VERSION 5.7 ;
BUSBITCHARS "[]" ;
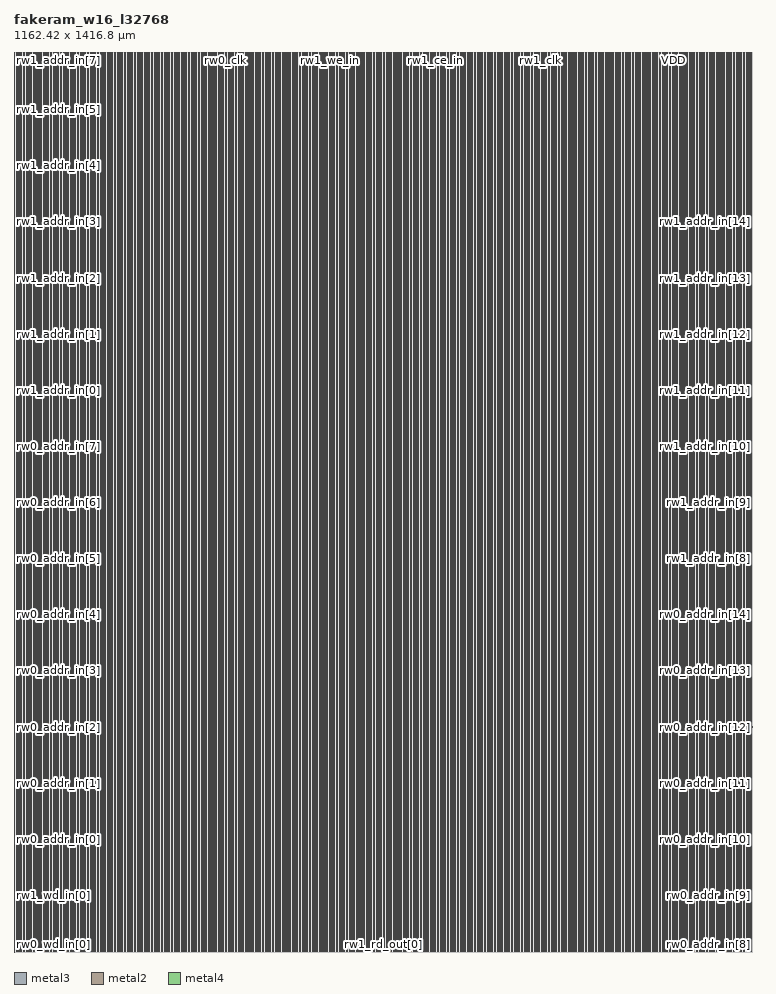
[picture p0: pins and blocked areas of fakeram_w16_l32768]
MACRO fakeram_w16_l32768
  FOREIGN fakeram_w16_l32768 0 0 ;
  SYMMETRY X Y R90 ;
  SIZE 1162.420 BY 1416.800 ;
  CLASS BLOCK ;
  PIN rw0_wd_in[0]
    DIRECTION INPUT ;
    USE SIGNAL ;
    SHAPE ABUTMENT ;
    PORT
      LAYER metal3 ;
      RECT 0.000 0.805 0.210 0.875 ;
    END
  END rw0_wd_in[0]
  PIN rw1_wd_in[0]
    DIRECTION INPUT ;
    USE SIGNAL ;
    SHAPE ABUTMENT ;
    PORT
      LAYER metal3 ;
      RECT 0.000 89.145 0.210 89.215 ;
    END
  END rw1_wd_in[0]
  PIN rw0_rd_out[0]
    DIRECTION OUTPUT ;
    USE SIGNAL ;
    SHAPE ABUTMENT ;
    PORT
      LAYER metal2 ;
      RECT 1.105 0.000 1.175 0.210 ;
    END
  END rw0_rd_out[0]
  PIN rw1_rd_out[0]
    DIRECTION OUTPUT ;
    USE SIGNAL ;
    SHAPE ABUTMENT ;
    PORT
      LAYER metal2 ;
      RECT 580.985 0.000 581.055 0.210 ;
    END
  END rw1_rd_out[0]
  PIN rw0_addr_in[0]
    DIRECTION INPUT ;
    USE SIGNAL ;
    SHAPE ABUTMENT ;
    PORT
      LAYER metal3 ;
      RECT 0.000 177.485 0.210 177.555 ;
    END
  END rw0_addr_in[0]
  PIN rw0_addr_in[1]
    DIRECTION INPUT ;
    USE SIGNAL ;
    SHAPE ABUTMENT ;
    PORT
      LAYER metal3 ;
      RECT 0.000 265.825 0.210 265.895 ;
    END
  END rw0_addr_in[1]
  PIN rw0_addr_in[2]
    DIRECTION INPUT ;
    USE SIGNAL ;
    SHAPE ABUTMENT ;
    PORT
      LAYER metal3 ;
      RECT 0.000 354.165 0.210 354.235 ;
    END
  END rw0_addr_in[2]
  PIN rw0_addr_in[3]
    DIRECTION INPUT ;
    USE SIGNAL ;
    SHAPE ABUTMENT ;
    PORT
      LAYER metal3 ;
      RECT 0.000 442.505 0.210 442.575 ;
    END
  END rw0_addr_in[3]
  PIN rw0_addr_in[4]
    DIRECTION INPUT ;
    USE SIGNAL ;
    SHAPE ABUTMENT ;
    PORT
      LAYER metal3 ;
      RECT 0.000 530.845 0.210 530.915 ;
    END
  END rw0_addr_in[4]
  PIN rw0_addr_in[5]
    DIRECTION INPUT ;
    USE SIGNAL ;
    SHAPE ABUTMENT ;
    PORT
      LAYER metal3 ;
      RECT 0.000 619.185 0.210 619.255 ;
    END
  END rw0_addr_in[5]
  PIN rw0_addr_in[6]
    DIRECTION INPUT ;
    USE SIGNAL ;
    SHAPE ABUTMENT ;
    PORT
      LAYER metal3 ;
      RECT 0.000 707.525 0.210 707.595 ;
    END
  END rw0_addr_in[6]
  PIN rw0_addr_in[7]
    DIRECTION INPUT ;
    USE SIGNAL ;
    SHAPE ABUTMENT ;
    PORT
      LAYER metal3 ;
      RECT 0.000 795.865 0.210 795.935 ;
    END
  END rw0_addr_in[7]
  PIN rw0_addr_in[8]
    DIRECTION INPUT ;
    USE SIGNAL ;
    SHAPE ABUTMENT ;
    PORT
      LAYER metal3 ;
      RECT 1162.210 0.805 1162.420 0.875 ;
    END
  END rw0_addr_in[8]
  PIN rw0_addr_in[9]
    DIRECTION INPUT ;
    USE SIGNAL ;
    SHAPE ABUTMENT ;
    PORT
      LAYER metal3 ;
      RECT 1162.210 89.145 1162.420 89.215 ;
    END
  END rw0_addr_in[9]
  PIN rw0_addr_in[10]
    DIRECTION INPUT ;
    USE SIGNAL ;
    SHAPE ABUTMENT ;
    PORT
      LAYER metal3 ;
      RECT 1162.210 177.485 1162.420 177.555 ;
    END
  END rw0_addr_in[10]
  PIN rw0_addr_in[11]
    DIRECTION INPUT ;
    USE SIGNAL ;
    SHAPE ABUTMENT ;
    PORT
      LAYER metal3 ;
      RECT 1162.210 265.825 1162.420 265.895 ;
    END
  END rw0_addr_in[11]
  PIN rw0_addr_in[12]
    DIRECTION INPUT ;
    USE SIGNAL ;
    SHAPE ABUTMENT ;
    PORT
      LAYER metal3 ;
      RECT 1162.210 354.165 1162.420 354.235 ;
    END
  END rw0_addr_in[12]
  PIN rw0_addr_in[13]
    DIRECTION INPUT ;
    USE SIGNAL ;
    SHAPE ABUTMENT ;
    PORT
      LAYER metal3 ;
      RECT 1162.210 442.505 1162.420 442.575 ;
    END
  END rw0_addr_in[13]
  PIN rw0_addr_in[14]
    DIRECTION INPUT ;
    USE SIGNAL ;
    SHAPE ABUTMENT ;
    PORT
      LAYER metal3 ;
      RECT 1162.210 530.845 1162.420 530.915 ;
    END
  END rw0_addr_in[14]
  PIN rw1_addr_in[0]
    DIRECTION INPUT ;
    USE SIGNAL ;
    SHAPE ABUTMENT ;
    PORT
      LAYER metal3 ;
      RECT 0.000 884.205 0.210 884.275 ;
    END
  END rw1_addr_in[0]
  PIN rw1_addr_in[1]
    DIRECTION INPUT ;
    USE SIGNAL ;
    SHAPE ABUTMENT ;
    PORT
      LAYER metal3 ;
      RECT 0.000 972.545 0.210 972.615 ;
    END
  END rw1_addr_in[1]
  PIN rw1_addr_in[2]
    DIRECTION INPUT ;
    USE SIGNAL ;
    SHAPE ABUTMENT ;
    PORT
      LAYER metal3 ;
      RECT 0.000 1060.885 0.210 1060.955 ;
    END
  END rw1_addr_in[2]
  PIN rw1_addr_in[3]
    DIRECTION INPUT ;
    USE SIGNAL ;
    SHAPE ABUTMENT ;
    PORT
      LAYER metal3 ;
      RECT 0.000 1149.225 0.210 1149.295 ;
    END
  END rw1_addr_in[3]
  PIN rw1_addr_in[4]
    DIRECTION INPUT ;
    USE SIGNAL ;
    SHAPE ABUTMENT ;
    PORT
      LAYER metal3 ;
      RECT 0.000 1237.565 0.210 1237.635 ;
    END
  END rw1_addr_in[4]
  PIN rw1_addr_in[5]
    DIRECTION INPUT ;
    USE SIGNAL ;
    SHAPE ABUTMENT ;
    PORT
      LAYER metal3 ;
      RECT 0.000 1325.905 0.210 1325.975 ;
    END
  END rw1_addr_in[5]
  PIN rw1_addr_in[6]
    DIRECTION INPUT ;
    USE SIGNAL ;
    SHAPE ABUTMENT ;
    PORT
      LAYER metal3 ;
      RECT 0.000 1414.245 0.210 1414.315 ;
    END
  END rw1_addr_in[6]
  PIN rw1_addr_in[7]
    DIRECTION INPUT ;
    USE SIGNAL ;
    SHAPE ABUTMENT ;
    PORT
      LAYER metal3 ;
      RECT 0.000 1502.585 0.210 1502.655 ;
    END
  END rw1_addr_in[7]
  PIN rw1_addr_in[8]
    DIRECTION INPUT ;
    USE SIGNAL ;
    SHAPE ABUTMENT ;
    PORT
      LAYER metal3 ;
      RECT 1162.210 619.185 1162.420 619.255 ;
    END
  END rw1_addr_in[8]
  PIN rw1_addr_in[9]
    DIRECTION INPUT ;
    USE SIGNAL ;
    SHAPE ABUTMENT ;
    PORT
      LAYER metal3 ;
      RECT 1162.210 707.525 1162.420 707.595 ;
    END
  END rw1_addr_in[9]
  PIN rw1_addr_in[10]
    DIRECTION INPUT ;
    USE SIGNAL ;
    SHAPE ABUTMENT ;
    PORT
      LAYER metal3 ;
      RECT 1162.210 795.865 1162.420 795.935 ;
    END
  END rw1_addr_in[10]
  PIN rw1_addr_in[11]
    DIRECTION INPUT ;
    USE SIGNAL ;
    SHAPE ABUTMENT ;
    PORT
      LAYER metal3 ;
      RECT 1162.210 884.205 1162.420 884.275 ;
    END
  END rw1_addr_in[11]
  PIN rw1_addr_in[12]
    DIRECTION INPUT ;
    USE SIGNAL ;
    SHAPE ABUTMENT ;
    PORT
      LAYER metal3 ;
      RECT 1162.210 972.545 1162.420 972.615 ;
    END
  END rw1_addr_in[12]
  PIN rw1_addr_in[13]
    DIRECTION INPUT ;
    USE SIGNAL ;
    SHAPE ABUTMENT ;
    PORT
      LAYER metal3 ;
      RECT 1162.210 1060.885 1162.420 1060.955 ;
    END
  END rw1_addr_in[13]
  PIN rw1_addr_in[14]
    DIRECTION INPUT ;
    USE SIGNAL ;
    SHAPE ABUTMENT ;
    PORT
      LAYER metal3 ;
      RECT 1162.210 1149.225 1162.420 1149.295 ;
    END
  END rw1_addr_in[14]
  PIN rw0_we_in
    DIRECTION INPUT ;
    USE SIGNAL ;
    SHAPE ABUTMENT ;
    PORT
      LAYER metal2 ;
      RECT 1.105 1416.590 1.175 1416.800 ;
    END
  END rw0_we_in
  PIN rw0_ce_in
    DIRECTION INPUT ;
    USE SIGNAL ;
    SHAPE ABUTMENT ;
    PORT
      LAYER metal2 ;
      RECT 166.785 1416.590 166.855 1416.800 ;
    END
  END rw0_ce_in
  PIN rw0_clk
    DIRECTION INPUT ;
    USE SIGNAL ;
    SHAPE ABUTMENT ;
    PORT
      LAYER metal2 ;
      RECT 332.465 1416.590 332.535 1416.800 ;
    END
  END rw0_clk
  PIN rw1_we_in
    DIRECTION INPUT ;
    USE SIGNAL ;
    SHAPE ABUTMENT ;
    PORT
      LAYER metal2 ;
      RECT 498.145 1416.590 498.215 1416.800 ;
    END
  END rw1_we_in
  PIN rw1_ce_in
    DIRECTION INPUT ;
    USE SIGNAL ;
    SHAPE ABUTMENT ;
    PORT
      LAYER metal2 ;
      RECT 663.825 1416.590 663.895 1416.800 ;
    END
  END rw1_ce_in
  PIN rw1_clk
    DIRECTION INPUT ;
    USE SIGNAL ;
    SHAPE ABUTMENT ;
    PORT
      LAYER metal2 ;
      RECT 829.505 1416.590 829.575 1416.800 ;
    END
  END rw1_clk
  PIN VSS
    DIRECTION INOUT ;
    USE GROUND ;
    PORT
      LAYER metal4 ;
      RECT 1.000 0.840 1.280 1415.960 ;
      RECT 3.240 0.840 3.520 1415.960 ;
      RECT 5.480 0.840 5.760 1415.960 ;
      RECT 7.720 0.840 8.000 1415.960 ;
      RECT 9.960 0.840 10.240 1415.960 ;
      RECT 12.200 0.840 12.480 1415.960 ;
      RECT 14.440 0.840 14.720 1415.960 ;
      RECT 16.680 0.840 16.960 1415.960 ;
      RECT 18.920 0.840 19.200 1415.960 ;
      RECT 21.160 0.840 21.440 1415.960 ;
      RECT 23.400 0.840 23.680 1415.960 ;
      RECT 25.640 0.840 25.920 1415.960 ;
      RECT 27.880 0.840 28.160 1415.960 ;
      RECT 30.120 0.840 30.400 1415.960 ;
      RECT 32.360 0.840 32.640 1415.960 ;
      RECT 34.600 0.840 34.880 1415.960 ;
      RECT 36.840 0.840 37.120 1415.960 ;
      RECT 39.080 0.840 39.360 1415.960 ;
      RECT 41.320 0.840 41.600 1415.960 ;
      RECT 43.560 0.840 43.840 1415.960 ;
      RECT 45.800 0.840 46.080 1415.960 ;
      RECT 48.040 0.840 48.320 1415.960 ;
      RECT 50.280 0.840 50.560 1415.960 ;
      RECT 52.520 0.840 52.800 1415.960 ;
      RECT 54.760 0.840 55.040 1415.960 ;
      RECT 57.000 0.840 57.280 1415.960 ;
      RECT 59.240 0.840 59.520 1415.960 ;
      RECT 61.480 0.840 61.760 1415.960 ;
      RECT 63.720 0.840 64.000 1415.960 ;
      RECT 65.960 0.840 66.240 1415.960 ;
      RECT 68.200 0.840 68.480 1415.960 ;
      RECT 70.440 0.840 70.720 1415.960 ;
      RECT 72.680 0.840 72.960 1415.960 ;
      RECT 74.920 0.840 75.200 1415.960 ;
      RECT 77.160 0.840 77.440 1415.960 ;
      RECT 79.400 0.840 79.680 1415.960 ;
      RECT 81.640 0.840 81.920 1415.960 ;
      RECT 83.880 0.840 84.160 1415.960 ;
      RECT 86.120 0.840 86.400 1415.960 ;
      RECT 88.360 0.840 88.640 1415.960 ;
      RECT 90.600 0.840 90.880 1415.960 ;
      RECT 92.840 0.840 93.120 1415.960 ;
      RECT 95.080 0.840 95.360 1415.960 ;
      RECT 97.320 0.840 97.600 1415.960 ;
      RECT 99.560 0.840 99.840 1415.960 ;
      RECT 101.800 0.840 102.080 1415.960 ;
      RECT 104.040 0.840 104.320 1415.960 ;
      RECT 106.280 0.840 106.560 1415.960 ;
      RECT 108.520 0.840 108.800 1415.960 ;
      RECT 110.760 0.840 111.040 1415.960 ;
      RECT 113.000 0.840 113.280 1415.960 ;
      RECT 115.240 0.840 115.520 1415.960 ;
      RECT 117.480 0.840 117.760 1415.960 ;
      RECT 119.720 0.840 120.000 1415.960 ;
      RECT 121.960 0.840 122.240 1415.960 ;
      RECT 124.200 0.840 124.480 1415.960 ;
      RECT 126.440 0.840 126.720 1415.960 ;
      RECT 128.680 0.840 128.960 1415.960 ;
      RECT 130.920 0.840 131.200 1415.960 ;
      RECT 133.160 0.840 133.440 1415.960 ;
      RECT 135.400 0.840 135.680 1415.960 ;
      RECT 137.640 0.840 137.920 1415.960 ;
      RECT 139.880 0.840 140.160 1415.960 ;
      RECT 142.120 0.840 142.400 1415.960 ;
      RECT 144.360 0.840 144.640 1415.960 ;
      RECT 146.600 0.840 146.880 1415.960 ;
      RECT 148.840 0.840 149.120 1415.960 ;
      RECT 151.080 0.840 151.360 1415.960 ;
      RECT 153.320 0.840 153.600 1415.960 ;
      RECT 155.560 0.840 155.840 1415.960 ;
      RECT 157.800 0.840 158.080 1415.960 ;
      RECT 160.040 0.840 160.320 1415.960 ;
      RECT 162.280 0.840 162.560 1415.960 ;
      RECT 164.520 0.840 164.800 1415.960 ;
      RECT 166.760 0.840 167.040 1415.960 ;
      RECT 169.000 0.840 169.280 1415.960 ;
      RECT 171.240 0.840 171.520 1415.960 ;
      RECT 173.480 0.840 173.760 1415.960 ;
      RECT 175.720 0.840 176.000 1415.960 ;
      RECT 177.960 0.840 178.240 1415.960 ;
      RECT 180.200 0.840 180.480 1415.960 ;
      RECT 182.440 0.840 182.720 1415.960 ;
      RECT 184.680 0.840 184.960 1415.960 ;
      RECT 186.920 0.840 187.200 1415.960 ;
      RECT 189.160 0.840 189.440 1415.960 ;
      RECT 191.400 0.840 191.680 1415.960 ;
      RECT 193.640 0.840 193.920 1415.960 ;
      RECT 195.880 0.840 196.160 1415.960 ;
      RECT 198.120 0.840 198.400 1415.960 ;
      RECT 200.360 0.840 200.640 1415.960 ;
      RECT 202.600 0.840 202.880 1415.960 ;
      RECT 204.840 0.840 205.120 1415.960 ;
      RECT 207.080 0.840 207.360 1415.960 ;
      RECT 209.320 0.840 209.600 1415.960 ;
      RECT 211.560 0.840 211.840 1415.960 ;
      RECT 213.800 0.840 214.080 1415.960 ;
      RECT 216.040 0.840 216.320 1415.960 ;
      RECT 218.280 0.840 218.560 1415.960 ;
      RECT 220.520 0.840 220.800 1415.960 ;
      RECT 222.760 0.840 223.040 1415.960 ;
      RECT 225.000 0.840 225.280 1415.960 ;
      RECT 227.240 0.840 227.520 1415.960 ;
      RECT 229.480 0.840 229.760 1415.960 ;
      RECT 231.720 0.840 232.000 1415.960 ;
      RECT 233.960 0.840 234.240 1415.960 ;
      RECT 236.200 0.840 236.480 1415.960 ;
      RECT 238.440 0.840 238.720 1415.960 ;
      RECT 240.680 0.840 240.960 1415.960 ;
      RECT 242.920 0.840 243.200 1415.960 ;
      RECT 245.160 0.840 245.440 1415.960 ;
      RECT 247.400 0.840 247.680 1415.960 ;
      RECT 249.640 0.840 249.920 1415.960 ;
      RECT 251.880 0.840 252.160 1415.960 ;
      RECT 254.120 0.840 254.400 1415.960 ;
      RECT 256.360 0.840 256.640 1415.960 ;
      RECT 258.600 0.840 258.880 1415.960 ;
      RECT 260.840 0.840 261.120 1415.960 ;
      RECT 263.080 0.840 263.360 1415.960 ;
      RECT 265.320 0.840 265.600 1415.960 ;
      RECT 267.560 0.840 267.840 1415.960 ;
      RECT 269.800 0.840 270.080 1415.960 ;
      RECT 272.040 0.840 272.320 1415.960 ;
      RECT 274.280 0.840 274.560 1415.960 ;
      RECT 276.520 0.840 276.800 1415.960 ;
      RECT 278.760 0.840 279.040 1415.960 ;
      RECT 281.000 0.840 281.280 1415.960 ;
      RECT 283.240 0.840 283.520 1415.960 ;
      RECT 285.480 0.840 285.760 1415.960 ;
      RECT 287.720 0.840 288.000 1415.960 ;
      RECT 289.960 0.840 290.240 1415.960 ;
      RECT 292.200 0.840 292.480 1415.960 ;
      RECT 294.440 0.840 294.720 1415.960 ;
      RECT 296.680 0.840 296.960 1415.960 ;
      RECT 298.920 0.840 299.200 1415.960 ;
      RECT 301.160 0.840 301.440 1415.960 ;
      RECT 303.400 0.840 303.680 1415.960 ;
      RECT 305.640 0.840 305.920 1415.960 ;
      RECT 307.880 0.840 308.160 1415.960 ;
      RECT 310.120 0.840 310.400 1415.960 ;
      RECT 312.360 0.840 312.640 1415.960 ;
      RECT 314.600 0.840 314.880 1415.960 ;
      RECT 316.840 0.840 317.120 1415.960 ;
      RECT 319.080 0.840 319.360 1415.960 ;
      RECT 321.320 0.840 321.600 1415.960 ;
      RECT 323.560 0.840 323.840 1415.960 ;
      RECT 325.800 0.840 326.080 1415.960 ;
      RECT 328.040 0.840 328.320 1415.960 ;
      RECT 330.280 0.840 330.560 1415.960 ;
      RECT 332.520 0.840 332.800 1415.960 ;
      RECT 334.760 0.840 335.040 1415.960 ;
      RECT 337.000 0.840 337.280 1415.960 ;
      RECT 339.240 0.840 339.520 1415.960 ;
      RECT 341.480 0.840 341.760 1415.960 ;
      RECT 343.720 0.840 344.000 1415.960 ;
      RECT 345.960 0.840 346.240 1415.960 ;
      RECT 348.200 0.840 348.480 1415.960 ;
      RECT 350.440 0.840 350.720 1415.960 ;
      RECT 352.680 0.840 352.960 1415.960 ;
      RECT 354.920 0.840 355.200 1415.960 ;
      RECT 357.160 0.840 357.440 1415.960 ;
      RECT 359.400 0.840 359.680 1415.960 ;
      RECT 361.640 0.840 361.920 1415.960 ;
      RECT 363.880 0.840 364.160 1415.960 ;
      RECT 366.120 0.840 366.400 1415.960 ;
      RECT 368.360 0.840 368.640 1415.960 ;
      RECT 370.600 0.840 370.880 1415.960 ;
      RECT 372.840 0.840 373.120 1415.960 ;
      RECT 375.080 0.840 375.360 1415.960 ;
      RECT 377.320 0.840 377.600 1415.960 ;
      RECT 379.560 0.840 379.840 1415.960 ;
      RECT 381.800 0.840 382.080 1415.960 ;
      RECT 384.040 0.840 384.320 1415.960 ;
      RECT 386.280 0.840 386.560 1415.960 ;
      RECT 388.520 0.840 388.800 1415.960 ;
      RECT 390.760 0.840 391.040 1415.960 ;
      RECT 393.000 0.840 393.280 1415.960 ;
      RECT 395.240 0.840 395.520 1415.960 ;
      RECT 397.480 0.840 397.760 1415.960 ;
      RECT 399.720 0.840 400.000 1415.960 ;
      RECT 401.960 0.840 402.240 1415.960 ;
      RECT 404.200 0.840 404.480 1415.960 ;
      RECT 406.440 0.840 406.720 1415.960 ;
      RECT 408.680 0.840 408.960 1415.960 ;
      RECT 410.920 0.840 411.200 1415.960 ;
      RECT 413.160 0.840 413.440 1415.960 ;
      RECT 415.400 0.840 415.680 1415.960 ;
      RECT 417.640 0.840 417.920 1415.960 ;
      RECT 419.880 0.840 420.160 1415.960 ;
      RECT 422.120 0.840 422.400 1415.960 ;
      RECT 424.360 0.840 424.640 1415.960 ;
      RECT 426.600 0.840 426.880 1415.960 ;
      RECT 428.840 0.840 429.120 1415.960 ;
      RECT 431.080 0.840 431.360 1415.960 ;
      RECT 433.320 0.840 433.600 1415.960 ;
      RECT 435.560 0.840 435.840 1415.960 ;
      RECT 437.800 0.840 438.080 1415.960 ;
      RECT 440.040 0.840 440.320 1415.960 ;
      RECT 442.280 0.840 442.560 1415.960 ;
      RECT 444.520 0.840 444.800 1415.960 ;
      RECT 446.760 0.840 447.040 1415.960 ;
      RECT 449.000 0.840 449.280 1415.960 ;
      RECT 451.240 0.840 451.520 1415.960 ;
      RECT 453.480 0.840 453.760 1415.960 ;
      RECT 455.720 0.840 456.000 1415.960 ;
      RECT 457.960 0.840 458.240 1415.960 ;
      RECT 460.200 0.840 460.480 1415.960 ;
      RECT 462.440 0.840 462.720 1415.960 ;
      RECT 464.680 0.840 464.960 1415.960 ;
      RECT 466.920 0.840 467.200 1415.960 ;
      RECT 469.160 0.840 469.440 1415.960 ;
      RECT 471.400 0.840 471.680 1415.960 ;
      RECT 473.640 0.840 473.920 1415.960 ;
      RECT 475.880 0.840 476.160 1415.960 ;
      RECT 478.120 0.840 478.400 1415.960 ;
      RECT 480.360 0.840 480.640 1415.960 ;
      RECT 482.600 0.840 482.880 1415.960 ;
      RECT 484.840 0.840 485.120 1415.960 ;
      RECT 487.080 0.840 487.360 1415.960 ;
      RECT 489.320 0.840 489.600 1415.960 ;
      RECT 491.560 0.840 491.840 1415.960 ;
      RECT 493.800 0.840 494.080 1415.960 ;
      RECT 496.040 0.840 496.320 1415.960 ;
      RECT 498.280 0.840 498.560 1415.960 ;
      RECT 500.520 0.840 500.800 1415.960 ;
      RECT 502.760 0.840 503.040 1415.960 ;
      RECT 505.000 0.840 505.280 1415.960 ;
      RECT 507.240 0.840 507.520 1415.960 ;
      RECT 509.480 0.840 509.760 1415.960 ;
      RECT 511.720 0.840 512.000 1415.960 ;
      RECT 513.960 0.840 514.240 1415.960 ;
      RECT 516.200 0.840 516.480 1415.960 ;
      RECT 518.440 0.840 518.720 1415.960 ;
      RECT 520.680 0.840 520.960 1415.960 ;
      RECT 522.920 0.840 523.200 1415.960 ;
      RECT 525.160 0.840 525.440 1415.960 ;
      RECT 527.400 0.840 527.680 1415.960 ;
      RECT 529.640 0.840 529.920 1415.960 ;
      RECT 531.880 0.840 532.160 1415.960 ;
      RECT 534.120 0.840 534.400 1415.960 ;
      RECT 536.360 0.840 536.640 1415.960 ;
      RECT 538.600 0.840 538.880 1415.960 ;
      RECT 540.840 0.840 541.120 1415.960 ;
      RECT 543.080 0.840 543.360 1415.960 ;
      RECT 545.320 0.840 545.600 1415.960 ;
      RECT 547.560 0.840 547.840 1415.960 ;
      RECT 549.800 0.840 550.080 1415.960 ;
      RECT 552.040 0.840 552.320 1415.960 ;
      RECT 554.280 0.840 554.560 1415.960 ;
      RECT 556.520 0.840 556.800 1415.960 ;
      RECT 558.760 0.840 559.040 1415.960 ;
      RECT 561.000 0.840 561.280 1415.960 ;
      RECT 563.240 0.840 563.520 1415.960 ;
      RECT 565.480 0.840 565.760 1415.960 ;
      RECT 567.720 0.840 568.000 1415.960 ;
      RECT 569.960 0.840 570.240 1415.960 ;
      RECT 572.200 0.840 572.480 1415.960 ;
      RECT 574.440 0.840 574.720 1415.960 ;
      RECT 576.680 0.840 576.960 1415.960 ;
      RECT 578.920 0.840 579.200 1415.960 ;
      RECT 581.160 0.840 581.440 1415.960 ;
      RECT 583.400 0.840 583.680 1415.960 ;
      RECT 585.640 0.840 585.920 1415.960 ;
      RECT 587.880 0.840 588.160 1415.960 ;
      RECT 590.120 0.840 590.400 1415.960 ;
      RECT 592.360 0.840 592.640 1415.960 ;
      RECT 594.600 0.840 594.880 1415.960 ;
      RECT 596.840 0.840 597.120 1415.960 ;
      RECT 599.080 0.840 599.360 1415.960 ;
      RECT 601.320 0.840 601.600 1415.960 ;
      RECT 603.560 0.840 603.840 1415.960 ;
      RECT 605.800 0.840 606.080 1415.960 ;
      RECT 608.040 0.840 608.320 1415.960 ;
      RECT 610.280 0.840 610.560 1415.960 ;
      RECT 612.520 0.840 612.800 1415.960 ;
      RECT 614.760 0.840 615.040 1415.960 ;
      RECT 617.000 0.840 617.280 1415.960 ;
      RECT 619.240 0.840 619.520 1415.960 ;
      RECT 621.480 0.840 621.760 1415.960 ;
      RECT 623.720 0.840 624.000 1415.960 ;
      RECT 625.960 0.840 626.240 1415.960 ;
      RECT 628.200 0.840 628.480 1415.960 ;
      RECT 630.440 0.840 630.720 1415.960 ;
      RECT 632.680 0.840 632.960 1415.960 ;
      RECT 634.920 0.840 635.200 1415.960 ;
      RECT 637.160 0.840 637.440 1415.960 ;
      RECT 639.400 0.840 639.680 1415.960 ;
      RECT 641.640 0.840 641.920 1415.960 ;
      RECT 643.880 0.840 644.160 1415.960 ;
      RECT 646.120 0.840 646.400 1415.960 ;
      RECT 648.360 0.840 648.640 1415.960 ;
      RECT 650.600 0.840 650.880 1415.960 ;
      RECT 652.840 0.840 653.120 1415.960 ;
      RECT 655.080 0.840 655.360 1415.960 ;
      RECT 657.320 0.840 657.600 1415.960 ;
      RECT 659.560 0.840 659.840 1415.960 ;
      RECT 661.800 0.840 662.080 1415.960 ;
      RECT 664.040 0.840 664.320 1415.960 ;
      RECT 666.280 0.840 666.560 1415.960 ;
      RECT 668.520 0.840 668.800 1415.960 ;
      RECT 670.760 0.840 671.040 1415.960 ;
      RECT 673.000 0.840 673.280 1415.960 ;
      RECT 675.240 0.840 675.520 1415.960 ;
      RECT 677.480 0.840 677.760 1415.960 ;
      RECT 679.720 0.840 680.000 1415.960 ;
      RECT 681.960 0.840 682.240 1415.960 ;
      RECT 684.200 0.840 684.480 1415.960 ;
      RECT 686.440 0.840 686.720 1415.960 ;
      RECT 688.680 0.840 688.960 1415.960 ;
      RECT 690.920 0.840 691.200 1415.960 ;
      RECT 693.160 0.840 693.440 1415.960 ;
      RECT 695.400 0.840 695.680 1415.960 ;
      RECT 697.640 0.840 697.920 1415.960 ;
      RECT 699.880 0.840 700.160 1415.960 ;
      RECT 702.120 0.840 702.400 1415.960 ;
      RECT 704.360 0.840 704.640 1415.960 ;
      RECT 706.600 0.840 706.880 1415.960 ;
      RECT 708.840 0.840 709.120 1415.960 ;
      RECT 711.080 0.840 711.360 1415.960 ;
      RECT 713.320 0.840 713.600 1415.960 ;
      RECT 715.560 0.840 715.840 1415.960 ;
      RECT 717.800 0.840 718.080 1415.960 ;
      RECT 720.040 0.840 720.320 1415.960 ;
      RECT 722.280 0.840 722.560 1415.960 ;
      RECT 724.520 0.840 724.800 1415.960 ;
      RECT 726.760 0.840 727.040 1415.960 ;
      RECT 729.000 0.840 729.280 1415.960 ;
      RECT 731.240 0.840 731.520 1415.960 ;
      RECT 733.480 0.840 733.760 1415.960 ;
      RECT 735.720 0.840 736.000 1415.960 ;
      RECT 737.960 0.840 738.240 1415.960 ;
      RECT 740.200 0.840 740.480 1415.960 ;
      RECT 742.440 0.840 742.720 1415.960 ;
      RECT 744.680 0.840 744.960 1415.960 ;
      RECT 746.920 0.840 747.200 1415.960 ;
      RECT 749.160 0.840 749.440 1415.960 ;
      RECT 751.400 0.840 751.680 1415.960 ;
      RECT 753.640 0.840 753.920 1415.960 ;
      RECT 755.880 0.840 756.160 1415.960 ;
      RECT 758.120 0.840 758.400 1415.960 ;
      RECT 760.360 0.840 760.640 1415.960 ;
      RECT 762.600 0.840 762.880 1415.960 ;
      RECT 764.840 0.840 765.120 1415.960 ;
      RECT 767.080 0.840 767.360 1415.960 ;
      RECT 769.320 0.840 769.600 1415.960 ;
      RECT 771.560 0.840 771.840 1415.960 ;
      RECT 773.800 0.840 774.080 1415.960 ;
      RECT 776.040 0.840 776.320 1415.960 ;
      RECT 778.280 0.840 778.560 1415.960 ;
      RECT 780.520 0.840 780.800 1415.960 ;
      RECT 782.760 0.840 783.040 1415.960 ;
      RECT 785.000 0.840 785.280 1415.960 ;
      RECT 787.240 0.840 787.520 1415.960 ;
      RECT 789.480 0.840 789.760 1415.960 ;
      RECT 791.720 0.840 792.000 1415.960 ;
      RECT 793.960 0.840 794.240 1415.960 ;
      RECT 796.200 0.840 796.480 1415.960 ;
      RECT 798.440 0.840 798.720 1415.960 ;
      RECT 800.680 0.840 800.960 1415.960 ;
      RECT 802.920 0.840 803.200 1415.960 ;
      RECT 805.160 0.840 805.440 1415.960 ;
      RECT 807.400 0.840 807.680 1415.960 ;
      RECT 809.640 0.840 809.920 1415.960 ;
      RECT 811.880 0.840 812.160 1415.960 ;
      RECT 814.120 0.840 814.400 1415.960 ;
      RECT 816.360 0.840 816.640 1415.960 ;
      RECT 818.600 0.840 818.880 1415.960 ;
      RECT 820.840 0.840 821.120 1415.960 ;
      RECT 823.080 0.840 823.360 1415.960 ;
      RECT 825.320 0.840 825.600 1415.960 ;
      RECT 827.560 0.840 827.840 1415.960 ;
      RECT 829.800 0.840 830.080 1415.960 ;
      RECT 832.040 0.840 832.320 1415.960 ;
      RECT 834.280 0.840 834.560 1415.960 ;
      RECT 836.520 0.840 836.800 1415.960 ;
      RECT 838.760 0.840 839.040 1415.960 ;
      RECT 841.000 0.840 841.280 1415.960 ;
      RECT 843.240 0.840 843.520 1415.960 ;
      RECT 845.480 0.840 845.760 1415.960 ;
      RECT 847.720 0.840 848.000 1415.960 ;
      RECT 849.960 0.840 850.240 1415.960 ;
      RECT 852.200 0.840 852.480 1415.960 ;
      RECT 854.440 0.840 854.720 1415.960 ;
      RECT 856.680 0.840 856.960 1415.960 ;
      RECT 858.920 0.840 859.200 1415.960 ;
      RECT 861.160 0.840 861.440 1415.960 ;
      RECT 863.400 0.840 863.680 1415.960 ;
      RECT 865.640 0.840 865.920 1415.960 ;
      RECT 867.880 0.840 868.160 1415.960 ;
      RECT 870.120 0.840 870.400 1415.960 ;
      RECT 872.360 0.840 872.640 1415.960 ;
      RECT 874.600 0.840 874.880 1415.960 ;
      RECT 876.840 0.840 877.120 1415.960 ;
      RECT 879.080 0.840 879.360 1415.960 ;
      RECT 881.320 0.840 881.600 1415.960 ;
      RECT 883.560 0.840 883.840 1415.960 ;
      RECT 885.800 0.840 886.080 1415.960 ;
      RECT 888.040 0.840 888.320 1415.960 ;
      RECT 890.280 0.840 890.560 1415.960 ;
      RECT 892.520 0.840 892.800 1415.960 ;
      RECT 894.760 0.840 895.040 1415.960 ;
      RECT 897.000 0.840 897.280 1415.960 ;
      RECT 899.240 0.840 899.520 1415.960 ;
      RECT 901.480 0.840 901.760 1415.960 ;
      RECT 903.720 0.840 904.000 1415.960 ;
      RECT 905.960 0.840 906.240 1415.960 ;
      RECT 908.200 0.840 908.480 1415.960 ;
      RECT 910.440 0.840 910.720 1415.960 ;
      RECT 912.680 0.840 912.960 1415.960 ;
      RECT 914.920 0.840 915.200 1415.960 ;
      RECT 917.160 0.840 917.440 1415.960 ;
      RECT 919.400 0.840 919.680 1415.960 ;
      RECT 921.640 0.840 921.920 1415.960 ;
      RECT 923.880 0.840 924.160 1415.960 ;
      RECT 926.120 0.840 926.400 1415.960 ;
      RECT 928.360 0.840 928.640 1415.960 ;
      RECT 930.600 0.840 930.880 1415.960 ;
      RECT 932.840 0.840 933.120 1415.960 ;
      RECT 935.080 0.840 935.360 1415.960 ;
      RECT 937.320 0.840 937.600 1415.960 ;
      RECT 939.560 0.840 939.840 1415.960 ;
      RECT 941.800 0.840 942.080 1415.960 ;
      RECT 944.040 0.840 944.320 1415.960 ;
      RECT 946.280 0.840 946.560 1415.960 ;
      RECT 948.520 0.840 948.800 1415.960 ;
      RECT 950.760 0.840 951.040 1415.960 ;
      RECT 953.000 0.840 953.280 1415.960 ;
      RECT 955.240 0.840 955.520 1415.960 ;
      RECT 957.480 0.840 957.760 1415.960 ;
      RECT 959.720 0.840 960.000 1415.960 ;
      RECT 961.960 0.840 962.240 1415.960 ;
      RECT 964.200 0.840 964.480 1415.960 ;
      RECT 966.440 0.840 966.720 1415.960 ;
      RECT 968.680 0.840 968.960 1415.960 ;
      RECT 970.920 0.840 971.200 1415.960 ;
      RECT 973.160 0.840 973.440 1415.960 ;
      RECT 975.400 0.840 975.680 1415.960 ;
      RECT 977.640 0.840 977.920 1415.960 ;
      RECT 979.880 0.840 980.160 1415.960 ;
      RECT 982.120 0.840 982.400 1415.960 ;
      RECT 984.360 0.840 984.640 1415.960 ;
      RECT 986.600 0.840 986.880 1415.960 ;
      RECT 988.840 0.840 989.120 1415.960 ;
      RECT 991.080 0.840 991.360 1415.960 ;
      RECT 993.320 0.840 993.600 1415.960 ;
      RECT 995.560 0.840 995.840 1415.960 ;
      RECT 997.800 0.840 998.080 1415.960 ;
      RECT 1000.040 0.840 1000.320 1415.960 ;
      RECT 1002.280 0.840 1002.560 1415.960 ;
      RECT 1004.520 0.840 1004.800 1415.960 ;
      RECT 1006.760 0.840 1007.040 1415.960 ;
      RECT 1009.000 0.840 1009.280 1415.960 ;
      RECT 1011.240 0.840 1011.520 1415.960 ;
      RECT 1013.480 0.840 1013.760 1415.960 ;
      RECT 1015.720 0.840 1016.000 1415.960 ;
      RECT 1017.960 0.840 1018.240 1415.960 ;
      RECT 1020.200 0.840 1020.480 1415.960 ;
      RECT 1022.440 0.840 1022.720 1415.960 ;
      RECT 1024.680 0.840 1024.960 1415.960 ;
      RECT 1026.920 0.840 1027.200 1415.960 ;
      RECT 1029.160 0.840 1029.440 1415.960 ;
      RECT 1031.400 0.840 1031.680 1415.960 ;
      RECT 1033.640 0.840 1033.920 1415.960 ;
      RECT 1035.880 0.840 1036.160 1415.960 ;
      RECT 1038.120 0.840 1038.400 1415.960 ;
      RECT 1040.360 0.840 1040.640 1415.960 ;
      RECT 1042.600 0.840 1042.880 1415.960 ;
      RECT 1044.840 0.840 1045.120 1415.960 ;
      RECT 1047.080 0.840 1047.360 1415.960 ;
      RECT 1049.320 0.840 1049.600 1415.960 ;
      RECT 1051.560 0.840 1051.840 1415.960 ;
      RECT 1053.800 0.840 1054.080 1415.960 ;
      RECT 1056.040 0.840 1056.320 1415.960 ;
      RECT 1058.280 0.840 1058.560 1415.960 ;
      RECT 1060.520 0.840 1060.800 1415.960 ;
      RECT 1062.760 0.840 1063.040 1415.960 ;
      RECT 1065.000 0.840 1065.280 1415.960 ;
      RECT 1067.240 0.840 1067.520 1415.960 ;
      RECT 1069.480 0.840 1069.760 1415.960 ;
      RECT 1071.720 0.840 1072.000 1415.960 ;
      RECT 1073.960 0.840 1074.240 1415.960 ;
      RECT 1076.200 0.840 1076.480 1415.960 ;
      RECT 1078.440 0.840 1078.720 1415.960 ;
      RECT 1080.680 0.840 1080.960 1415.960 ;
      RECT 1082.920 0.840 1083.200 1415.960 ;
      RECT 1085.160 0.840 1085.440 1415.960 ;
      RECT 1087.400 0.840 1087.680 1415.960 ;
      RECT 1089.640 0.840 1089.920 1415.960 ;
      RECT 1091.880 0.840 1092.160 1415.960 ;
      RECT 1094.120 0.840 1094.400 1415.960 ;
      RECT 1096.360 0.840 1096.640 1415.960 ;
      RECT 1098.600 0.840 1098.880 1415.960 ;
      RECT 1100.840 0.840 1101.120 1415.960 ;
      RECT 1103.080 0.840 1103.360 1415.960 ;
      RECT 1105.320 0.840 1105.600 1415.960 ;
      RECT 1107.560 0.840 1107.840 1415.960 ;
      RECT 1109.800 0.840 1110.080 1415.960 ;
      RECT 1112.040 0.840 1112.320 1415.960 ;
      RECT 1114.280 0.840 1114.560 1415.960 ;
      RECT 1116.520 0.840 1116.800 1415.960 ;
      RECT 1118.760 0.840 1119.040 1415.960 ;
      RECT 1121.000 0.840 1121.280 1415.960 ;
      RECT 1123.240 0.840 1123.520 1415.960 ;
      RECT 1125.480 0.840 1125.760 1415.960 ;
      RECT 1127.720 0.840 1128.000 1415.960 ;
      RECT 1129.960 0.840 1130.240 1415.960 ;
      RECT 1132.200 0.840 1132.480 1415.960 ;
      RECT 1134.440 0.840 1134.720 1415.960 ;
      RECT 1136.680 0.840 1136.960 1415.960 ;
      RECT 1138.920 0.840 1139.200 1415.960 ;
      RECT 1141.160 0.840 1141.440 1415.960 ;
      RECT 1143.400 0.840 1143.680 1415.960 ;
      RECT 1145.640 0.840 1145.920 1415.960 ;
      RECT 1147.880 0.840 1148.160 1415.960 ;
      RECT 1150.120 0.840 1150.400 1415.960 ;
      RECT 1152.360 0.840 1152.640 1415.960 ;
      RECT 1154.600 0.840 1154.880 1415.960 ;
      RECT 1156.840 0.840 1157.120 1415.960 ;
      RECT 1159.080 0.840 1159.360 1415.960 ;
      RECT 1161.320 0.840 1161.600 1415.960 ;
    END
  END VSS
  PIN VDD
    DIRECTION INOUT ;
    USE POWER ;
    PORT
      LAYER metal4 ;
      RECT 1.000 0.840 1.280 1415.960 ;
      RECT 3.240 0.840 3.520 1415.960 ;
      RECT 5.480 0.840 5.760 1415.960 ;
      RECT 7.720 0.840 8.000 1415.960 ;
      RECT 9.960 0.840 10.240 1415.960 ;
      RECT 12.200 0.840 12.480 1415.960 ;
      RECT 14.440 0.840 14.720 1415.960 ;
      RECT 16.680 0.840 16.960 1415.960 ;
      RECT 18.920 0.840 19.200 1415.960 ;
      RECT 21.160 0.840 21.440 1415.960 ;
      RECT 23.400 0.840 23.680 1415.960 ;
      RECT 25.640 0.840 25.920 1415.960 ;
      RECT 27.880 0.840 28.160 1415.960 ;
      RECT 30.120 0.840 30.400 1415.960 ;
      RECT 32.360 0.840 32.640 1415.960 ;
      RECT 34.600 0.840 34.880 1415.960 ;
      RECT 36.840 0.840 37.120 1415.960 ;
      RECT 39.080 0.840 39.360 1415.960 ;
      RECT 41.320 0.840 41.600 1415.960 ;
      RECT 43.560 0.840 43.840 1415.960 ;
      RECT 45.800 0.840 46.080 1415.960 ;
      RECT 48.040 0.840 48.320 1415.960 ;
      RECT 50.280 0.840 50.560 1415.960 ;
      RECT 52.520 0.840 52.800 1415.960 ;
      RECT 54.760 0.840 55.040 1415.960 ;
      RECT 57.000 0.840 57.280 1415.960 ;
      RECT 59.240 0.840 59.520 1415.960 ;
      RECT 61.480 0.840 61.760 1415.960 ;
      RECT 63.720 0.840 64.000 1415.960 ;
      RECT 65.960 0.840 66.240 1415.960 ;
      RECT 68.200 0.840 68.480 1415.960 ;
      RECT 70.440 0.840 70.720 1415.960 ;
      RECT 72.680 0.840 72.960 1415.960 ;
      RECT 74.920 0.840 75.200 1415.960 ;
      RECT 77.160 0.840 77.440 1415.960 ;
      RECT 79.400 0.840 79.680 1415.960 ;
      RECT 81.640 0.840 81.920 1415.960 ;
      RECT 83.880 0.840 84.160 1415.960 ;
      RECT 86.120 0.840 86.400 1415.960 ;
      RECT 88.360 0.840 88.640 1415.960 ;
      RECT 90.600 0.840 90.880 1415.960 ;
      RECT 92.840 0.840 93.120 1415.960 ;
      RECT 95.080 0.840 95.360 1415.960 ;
      RECT 97.320 0.840 97.600 1415.960 ;
      RECT 99.560 0.840 99.840 1415.960 ;
      RECT 101.800 0.840 102.080 1415.960 ;
      RECT 104.040 0.840 104.320 1415.960 ;
      RECT 106.280 0.840 106.560 1415.960 ;
      RECT 108.520 0.840 108.800 1415.960 ;
      RECT 110.760 0.840 111.040 1415.960 ;
      RECT 113.000 0.840 113.280 1415.960 ;
      RECT 115.240 0.840 115.520 1415.960 ;
      RECT 117.480 0.840 117.760 1415.960 ;
      RECT 119.720 0.840 120.000 1415.960 ;
      RECT 121.960 0.840 122.240 1415.960 ;
      RECT 124.200 0.840 124.480 1415.960 ;
      RECT 126.440 0.840 126.720 1415.960 ;
      RECT 128.680 0.840 128.960 1415.960 ;
      RECT 130.920 0.840 131.200 1415.960 ;
      RECT 133.160 0.840 133.440 1415.960 ;
      RECT 135.400 0.840 135.680 1415.960 ;
      RECT 137.640 0.840 137.920 1415.960 ;
      RECT 139.880 0.840 140.160 1415.960 ;
      RECT 142.120 0.840 142.400 1415.960 ;
      RECT 144.360 0.840 144.640 1415.960 ;
      RECT 146.600 0.840 146.880 1415.960 ;
      RECT 148.840 0.840 149.120 1415.960 ;
      RECT 151.080 0.840 151.360 1415.960 ;
      RECT 153.320 0.840 153.600 1415.960 ;
      RECT 155.560 0.840 155.840 1415.960 ;
      RECT 157.800 0.840 158.080 1415.960 ;
      RECT 160.040 0.840 160.320 1415.960 ;
      RECT 162.280 0.840 162.560 1415.960 ;
      RECT 164.520 0.840 164.800 1415.960 ;
      RECT 166.760 0.840 167.040 1415.960 ;
      RECT 169.000 0.840 169.280 1415.960 ;
      RECT 171.240 0.840 171.520 1415.960 ;
      RECT 173.480 0.840 173.760 1415.960 ;
      RECT 175.720 0.840 176.000 1415.960 ;
      RECT 177.960 0.840 178.240 1415.960 ;
      RECT 180.200 0.840 180.480 1415.960 ;
      RECT 182.440 0.840 182.720 1415.960 ;
      RECT 184.680 0.840 184.960 1415.960 ;
      RECT 186.920 0.840 187.200 1415.960 ;
      RECT 189.160 0.840 189.440 1415.960 ;
      RECT 191.400 0.840 191.680 1415.960 ;
      RECT 193.640 0.840 193.920 1415.960 ;
      RECT 195.880 0.840 196.160 1415.960 ;
      RECT 198.120 0.840 198.400 1415.960 ;
      RECT 200.360 0.840 200.640 1415.960 ;
      RECT 202.600 0.840 202.880 1415.960 ;
      RECT 204.840 0.840 205.120 1415.960 ;
      RECT 207.080 0.840 207.360 1415.960 ;
      RECT 209.320 0.840 209.600 1415.960 ;
      RECT 211.560 0.840 211.840 1415.960 ;
      RECT 213.800 0.840 214.080 1415.960 ;
      RECT 216.040 0.840 216.320 1415.960 ;
      RECT 218.280 0.840 218.560 1415.960 ;
      RECT 220.520 0.840 220.800 1415.960 ;
      RECT 222.760 0.840 223.040 1415.960 ;
      RECT 225.000 0.840 225.280 1415.960 ;
      RECT 227.240 0.840 227.520 1415.960 ;
      RECT 229.480 0.840 229.760 1415.960 ;
      RECT 231.720 0.840 232.000 1415.960 ;
      RECT 233.960 0.840 234.240 1415.960 ;
      RECT 236.200 0.840 236.480 1415.960 ;
      RECT 238.440 0.840 238.720 1415.960 ;
      RECT 240.680 0.840 240.960 1415.960 ;
      RECT 242.920 0.840 243.200 1415.960 ;
      RECT 245.160 0.840 245.440 1415.960 ;
      RECT 247.400 0.840 247.680 1415.960 ;
      RECT 249.640 0.840 249.920 1415.960 ;
      RECT 251.880 0.840 252.160 1415.960 ;
      RECT 254.120 0.840 254.400 1415.960 ;
      RECT 256.360 0.840 256.640 1415.960 ;
      RECT 258.600 0.840 258.880 1415.960 ;
      RECT 260.840 0.840 261.120 1415.960 ;
      RECT 263.080 0.840 263.360 1415.960 ;
      RECT 265.320 0.840 265.600 1415.960 ;
      RECT 267.560 0.840 267.840 1415.960 ;
      RECT 269.800 0.840 270.080 1415.960 ;
      RECT 272.040 0.840 272.320 1415.960 ;
      RECT 274.280 0.840 274.560 1415.960 ;
      RECT 276.520 0.840 276.800 1415.960 ;
      RECT 278.760 0.840 279.040 1415.960 ;
      RECT 281.000 0.840 281.280 1415.960 ;
      RECT 283.240 0.840 283.520 1415.960 ;
      RECT 285.480 0.840 285.760 1415.960 ;
      RECT 287.720 0.840 288.000 1415.960 ;
      RECT 289.960 0.840 290.240 1415.960 ;
      RECT 292.200 0.840 292.480 1415.960 ;
      RECT 294.440 0.840 294.720 1415.960 ;
      RECT 296.680 0.840 296.960 1415.960 ;
      RECT 298.920 0.840 299.200 1415.960 ;
      RECT 301.160 0.840 301.440 1415.960 ;
      RECT 303.400 0.840 303.680 1415.960 ;
      RECT 305.640 0.840 305.920 1415.960 ;
      RECT 307.880 0.840 308.160 1415.960 ;
      RECT 310.120 0.840 310.400 1415.960 ;
      RECT 312.360 0.840 312.640 1415.960 ;
      RECT 314.600 0.840 314.880 1415.960 ;
      RECT 316.840 0.840 317.120 1415.960 ;
      RECT 319.080 0.840 319.360 1415.960 ;
      RECT 321.320 0.840 321.600 1415.960 ;
      RECT 323.560 0.840 323.840 1415.960 ;
      RECT 325.800 0.840 326.080 1415.960 ;
      RECT 328.040 0.840 328.320 1415.960 ;
      RECT 330.280 0.840 330.560 1415.960 ;
      RECT 332.520 0.840 332.800 1415.960 ;
      RECT 334.760 0.840 335.040 1415.960 ;
      RECT 337.000 0.840 337.280 1415.960 ;
      RECT 339.240 0.840 339.520 1415.960 ;
      RECT 341.480 0.840 341.760 1415.960 ;
      RECT 343.720 0.840 344.000 1415.960 ;
      RECT 345.960 0.840 346.240 1415.960 ;
      RECT 348.200 0.840 348.480 1415.960 ;
      RECT 350.440 0.840 350.720 1415.960 ;
      RECT 352.680 0.840 352.960 1415.960 ;
      RECT 354.920 0.840 355.200 1415.960 ;
      RECT 357.160 0.840 357.440 1415.960 ;
      RECT 359.400 0.840 359.680 1415.960 ;
      RECT 361.640 0.840 361.920 1415.960 ;
      RECT 363.880 0.840 364.160 1415.960 ;
      RECT 366.120 0.840 366.400 1415.960 ;
      RECT 368.360 0.840 368.640 1415.960 ;
      RECT 370.600 0.840 370.880 1415.960 ;
      RECT 372.840 0.840 373.120 1415.960 ;
      RECT 375.080 0.840 375.360 1415.960 ;
      RECT 377.320 0.840 377.600 1415.960 ;
      RECT 379.560 0.840 379.840 1415.960 ;
      RECT 381.800 0.840 382.080 1415.960 ;
      RECT 384.040 0.840 384.320 1415.960 ;
      RECT 386.280 0.840 386.560 1415.960 ;
      RECT 388.520 0.840 388.800 1415.960 ;
      RECT 390.760 0.840 391.040 1415.960 ;
      RECT 393.000 0.840 393.280 1415.960 ;
      RECT 395.240 0.840 395.520 1415.960 ;
      RECT 397.480 0.840 397.760 1415.960 ;
      RECT 399.720 0.840 400.000 1415.960 ;
      RECT 401.960 0.840 402.240 1415.960 ;
      RECT 404.200 0.840 404.480 1415.960 ;
      RECT 406.440 0.840 406.720 1415.960 ;
      RECT 408.680 0.840 408.960 1415.960 ;
      RECT 410.920 0.840 411.200 1415.960 ;
      RECT 413.160 0.840 413.440 1415.960 ;
      RECT 415.400 0.840 415.680 1415.960 ;
      RECT 417.640 0.840 417.920 1415.960 ;
      RECT 419.880 0.840 420.160 1415.960 ;
      RECT 422.120 0.840 422.400 1415.960 ;
      RECT 424.360 0.840 424.640 1415.960 ;
      RECT 426.600 0.840 426.880 1415.960 ;
      RECT 428.840 0.840 429.120 1415.960 ;
      RECT 431.080 0.840 431.360 1415.960 ;
      RECT 433.320 0.840 433.600 1415.960 ;
      RECT 435.560 0.840 435.840 1415.960 ;
      RECT 437.800 0.840 438.080 1415.960 ;
      RECT 440.040 0.840 440.320 1415.960 ;
      RECT 442.280 0.840 442.560 1415.960 ;
      RECT 444.520 0.840 444.800 1415.960 ;
      RECT 446.760 0.840 447.040 1415.960 ;
      RECT 449.000 0.840 449.280 1415.960 ;
      RECT 451.240 0.840 451.520 1415.960 ;
      RECT 453.480 0.840 453.760 1415.960 ;
      RECT 455.720 0.840 456.000 1415.960 ;
      RECT 457.960 0.840 458.240 1415.960 ;
      RECT 460.200 0.840 460.480 1415.960 ;
      RECT 462.440 0.840 462.720 1415.960 ;
      RECT 464.680 0.840 464.960 1415.960 ;
      RECT 466.920 0.840 467.200 1415.960 ;
      RECT 469.160 0.840 469.440 1415.960 ;
      RECT 471.400 0.840 471.680 1415.960 ;
      RECT 473.640 0.840 473.920 1415.960 ;
      RECT 475.880 0.840 476.160 1415.960 ;
      RECT 478.120 0.840 478.400 1415.960 ;
      RECT 480.360 0.840 480.640 1415.960 ;
      RECT 482.600 0.840 482.880 1415.960 ;
      RECT 484.840 0.840 485.120 1415.960 ;
      RECT 487.080 0.840 487.360 1415.960 ;
      RECT 489.320 0.840 489.600 1415.960 ;
      RECT 491.560 0.840 491.840 1415.960 ;
      RECT 493.800 0.840 494.080 1415.960 ;
      RECT 496.040 0.840 496.320 1415.960 ;
      RECT 498.280 0.840 498.560 1415.960 ;
      RECT 500.520 0.840 500.800 1415.960 ;
      RECT 502.760 0.840 503.040 1415.960 ;
      RECT 505.000 0.840 505.280 1415.960 ;
      RECT 507.240 0.840 507.520 1415.960 ;
      RECT 509.480 0.840 509.760 1415.960 ;
      RECT 511.720 0.840 512.000 1415.960 ;
      RECT 513.960 0.840 514.240 1415.960 ;
      RECT 516.200 0.840 516.480 1415.960 ;
      RECT 518.440 0.840 518.720 1415.960 ;
      RECT 520.680 0.840 520.960 1415.960 ;
      RECT 522.920 0.840 523.200 1415.960 ;
      RECT 525.160 0.840 525.440 1415.960 ;
      RECT 527.400 0.840 527.680 1415.960 ;
      RECT 529.640 0.840 529.920 1415.960 ;
      RECT 531.880 0.840 532.160 1415.960 ;
      RECT 534.120 0.840 534.400 1415.960 ;
      RECT 536.360 0.840 536.640 1415.960 ;
      RECT 538.600 0.840 538.880 1415.960 ;
      RECT 540.840 0.840 541.120 1415.960 ;
      RECT 543.080 0.840 543.360 1415.960 ;
      RECT 545.320 0.840 545.600 1415.960 ;
      RECT 547.560 0.840 547.840 1415.960 ;
      RECT 549.800 0.840 550.080 1415.960 ;
      RECT 552.040 0.840 552.320 1415.960 ;
      RECT 554.280 0.840 554.560 1415.960 ;
      RECT 556.520 0.840 556.800 1415.960 ;
      RECT 558.760 0.840 559.040 1415.960 ;
      RECT 561.000 0.840 561.280 1415.960 ;
      RECT 563.240 0.840 563.520 1415.960 ;
      RECT 565.480 0.840 565.760 1415.960 ;
      RECT 567.720 0.840 568.000 1415.960 ;
      RECT 569.960 0.840 570.240 1415.960 ;
      RECT 572.200 0.840 572.480 1415.960 ;
      RECT 574.440 0.840 574.720 1415.960 ;
      RECT 576.680 0.840 576.960 1415.960 ;
      RECT 578.920 0.840 579.200 1415.960 ;
      RECT 581.160 0.840 581.440 1415.960 ;
      RECT 583.400 0.840 583.680 1415.960 ;
      RECT 585.640 0.840 585.920 1415.960 ;
      RECT 587.880 0.840 588.160 1415.960 ;
      RECT 590.120 0.840 590.400 1415.960 ;
      RECT 592.360 0.840 592.640 1415.960 ;
      RECT 594.600 0.840 594.880 1415.960 ;
      RECT 596.840 0.840 597.120 1415.960 ;
      RECT 599.080 0.840 599.360 1415.960 ;
      RECT 601.320 0.840 601.600 1415.960 ;
      RECT 603.560 0.840 603.840 1415.960 ;
      RECT 605.800 0.840 606.080 1415.960 ;
      RECT 608.040 0.840 608.320 1415.960 ;
      RECT 610.280 0.840 610.560 1415.960 ;
      RECT 612.520 0.840 612.800 1415.960 ;
      RECT 614.760 0.840 615.040 1415.960 ;
      RECT 617.000 0.840 617.280 1415.960 ;
      RECT 619.240 0.840 619.520 1415.960 ;
      RECT 621.480 0.840 621.760 1415.960 ;
      RECT 623.720 0.840 624.000 1415.960 ;
      RECT 625.960 0.840 626.240 1415.960 ;
      RECT 628.200 0.840 628.480 1415.960 ;
      RECT 630.440 0.840 630.720 1415.960 ;
      RECT 632.680 0.840 632.960 1415.960 ;
      RECT 634.920 0.840 635.200 1415.960 ;
      RECT 637.160 0.840 637.440 1415.960 ;
      RECT 639.400 0.840 639.680 1415.960 ;
      RECT 641.640 0.840 641.920 1415.960 ;
      RECT 643.880 0.840 644.160 1415.960 ;
      RECT 646.120 0.840 646.400 1415.960 ;
      RECT 648.360 0.840 648.640 1415.960 ;
      RECT 650.600 0.840 650.880 1415.960 ;
      RECT 652.840 0.840 653.120 1415.960 ;
      RECT 655.080 0.840 655.360 1415.960 ;
      RECT 657.320 0.840 657.600 1415.960 ;
      RECT 659.560 0.840 659.840 1415.960 ;
      RECT 661.800 0.840 662.080 1415.960 ;
      RECT 664.040 0.840 664.320 1415.960 ;
      RECT 666.280 0.840 666.560 1415.960 ;
      RECT 668.520 0.840 668.800 1415.960 ;
      RECT 670.760 0.840 671.040 1415.960 ;
      RECT 673.000 0.840 673.280 1415.960 ;
      RECT 675.240 0.840 675.520 1415.960 ;
      RECT 677.480 0.840 677.760 1415.960 ;
      RECT 679.720 0.840 680.000 1415.960 ;
      RECT 681.960 0.840 682.240 1415.960 ;
      RECT 684.200 0.840 684.480 1415.960 ;
      RECT 686.440 0.840 686.720 1415.960 ;
      RECT 688.680 0.840 688.960 1415.960 ;
      RECT 690.920 0.840 691.200 1415.960 ;
      RECT 693.160 0.840 693.440 1415.960 ;
      RECT 695.400 0.840 695.680 1415.960 ;
      RECT 697.640 0.840 697.920 1415.960 ;
      RECT 699.880 0.840 700.160 1415.960 ;
      RECT 702.120 0.840 702.400 1415.960 ;
      RECT 704.360 0.840 704.640 1415.960 ;
      RECT 706.600 0.840 706.880 1415.960 ;
      RECT 708.840 0.840 709.120 1415.960 ;
      RECT 711.080 0.840 711.360 1415.960 ;
      RECT 713.320 0.840 713.600 1415.960 ;
      RECT 715.560 0.840 715.840 1415.960 ;
      RECT 717.800 0.840 718.080 1415.960 ;
      RECT 720.040 0.840 720.320 1415.960 ;
      RECT 722.280 0.840 722.560 1415.960 ;
      RECT 724.520 0.840 724.800 1415.960 ;
      RECT 726.760 0.840 727.040 1415.960 ;
      RECT 729.000 0.840 729.280 1415.960 ;
      RECT 731.240 0.840 731.520 1415.960 ;
      RECT 733.480 0.840 733.760 1415.960 ;
      RECT 735.720 0.840 736.000 1415.960 ;
      RECT 737.960 0.840 738.240 1415.960 ;
      RECT 740.200 0.840 740.480 1415.960 ;
      RECT 742.440 0.840 742.720 1415.960 ;
      RECT 744.680 0.840 744.960 1415.960 ;
      RECT 746.920 0.840 747.200 1415.960 ;
      RECT 749.160 0.840 749.440 1415.960 ;
      RECT 751.400 0.840 751.680 1415.960 ;
      RECT 753.640 0.840 753.920 1415.960 ;
      RECT 755.880 0.840 756.160 1415.960 ;
      RECT 758.120 0.840 758.400 1415.960 ;
      RECT 760.360 0.840 760.640 1415.960 ;
      RECT 762.600 0.840 762.880 1415.960 ;
      RECT 764.840 0.840 765.120 1415.960 ;
      RECT 767.080 0.840 767.360 1415.960 ;
      RECT 769.320 0.840 769.600 1415.960 ;
      RECT 771.560 0.840 771.840 1415.960 ;
      RECT 773.800 0.840 774.080 1415.960 ;
      RECT 776.040 0.840 776.320 1415.960 ;
      RECT 778.280 0.840 778.560 1415.960 ;
      RECT 780.520 0.840 780.800 1415.960 ;
      RECT 782.760 0.840 783.040 1415.960 ;
      RECT 785.000 0.840 785.280 1415.960 ;
      RECT 787.240 0.840 787.520 1415.960 ;
      RECT 789.480 0.840 789.760 1415.960 ;
      RECT 791.720 0.840 792.000 1415.960 ;
      RECT 793.960 0.840 794.240 1415.960 ;
      RECT 796.200 0.840 796.480 1415.960 ;
      RECT 798.440 0.840 798.720 1415.960 ;
      RECT 800.680 0.840 800.960 1415.960 ;
      RECT 802.920 0.840 803.200 1415.960 ;
      RECT 805.160 0.840 805.440 1415.960 ;
      RECT 807.400 0.840 807.680 1415.960 ;
      RECT 809.640 0.840 809.920 1415.960 ;
      RECT 811.880 0.840 812.160 1415.960 ;
      RECT 814.120 0.840 814.400 1415.960 ;
      RECT 816.360 0.840 816.640 1415.960 ;
      RECT 818.600 0.840 818.880 1415.960 ;
      RECT 820.840 0.840 821.120 1415.960 ;
      RECT 823.080 0.840 823.360 1415.960 ;
      RECT 825.320 0.840 825.600 1415.960 ;
      RECT 827.560 0.840 827.840 1415.960 ;
      RECT 829.800 0.840 830.080 1415.960 ;
      RECT 832.040 0.840 832.320 1415.960 ;
      RECT 834.280 0.840 834.560 1415.960 ;
      RECT 836.520 0.840 836.800 1415.960 ;
      RECT 838.760 0.840 839.040 1415.960 ;
      RECT 841.000 0.840 841.280 1415.960 ;
      RECT 843.240 0.840 843.520 1415.960 ;
      RECT 845.480 0.840 845.760 1415.960 ;
      RECT 847.720 0.840 848.000 1415.960 ;
      RECT 849.960 0.840 850.240 1415.960 ;
      RECT 852.200 0.840 852.480 1415.960 ;
      RECT 854.440 0.840 854.720 1415.960 ;
      RECT 856.680 0.840 856.960 1415.960 ;
      RECT 858.920 0.840 859.200 1415.960 ;
      RECT 861.160 0.840 861.440 1415.960 ;
      RECT 863.400 0.840 863.680 1415.960 ;
      RECT 865.640 0.840 865.920 1415.960 ;
      RECT 867.880 0.840 868.160 1415.960 ;
      RECT 870.120 0.840 870.400 1415.960 ;
      RECT 872.360 0.840 872.640 1415.960 ;
      RECT 874.600 0.840 874.880 1415.960 ;
      RECT 876.840 0.840 877.120 1415.960 ;
      RECT 879.080 0.840 879.360 1415.960 ;
      RECT 881.320 0.840 881.600 1415.960 ;
      RECT 883.560 0.840 883.840 1415.960 ;
      RECT 885.800 0.840 886.080 1415.960 ;
      RECT 888.040 0.840 888.320 1415.960 ;
      RECT 890.280 0.840 890.560 1415.960 ;
      RECT 892.520 0.840 892.800 1415.960 ;
      RECT 894.760 0.840 895.040 1415.960 ;
      RECT 897.000 0.840 897.280 1415.960 ;
      RECT 899.240 0.840 899.520 1415.960 ;
      RECT 901.480 0.840 901.760 1415.960 ;
      RECT 903.720 0.840 904.000 1415.960 ;
      RECT 905.960 0.840 906.240 1415.960 ;
      RECT 908.200 0.840 908.480 1415.960 ;
      RECT 910.440 0.840 910.720 1415.960 ;
      RECT 912.680 0.840 912.960 1415.960 ;
      RECT 914.920 0.840 915.200 1415.960 ;
      RECT 917.160 0.840 917.440 1415.960 ;
      RECT 919.400 0.840 919.680 1415.960 ;
      RECT 921.640 0.840 921.920 1415.960 ;
      RECT 923.880 0.840 924.160 1415.960 ;
      RECT 926.120 0.840 926.400 1415.960 ;
      RECT 928.360 0.840 928.640 1415.960 ;
      RECT 930.600 0.840 930.880 1415.960 ;
      RECT 932.840 0.840 933.120 1415.960 ;
      RECT 935.080 0.840 935.360 1415.960 ;
      RECT 937.320 0.840 937.600 1415.960 ;
      RECT 939.560 0.840 939.840 1415.960 ;
      RECT 941.800 0.840 942.080 1415.960 ;
      RECT 944.040 0.840 944.320 1415.960 ;
      RECT 946.280 0.840 946.560 1415.960 ;
      RECT 948.520 0.840 948.800 1415.960 ;
      RECT 950.760 0.840 951.040 1415.960 ;
      RECT 953.000 0.840 953.280 1415.960 ;
      RECT 955.240 0.840 955.520 1415.960 ;
      RECT 957.480 0.840 957.760 1415.960 ;
      RECT 959.720 0.840 960.000 1415.960 ;
      RECT 961.960 0.840 962.240 1415.960 ;
      RECT 964.200 0.840 964.480 1415.960 ;
      RECT 966.440 0.840 966.720 1415.960 ;
      RECT 968.680 0.840 968.960 1415.960 ;
      RECT 970.920 0.840 971.200 1415.960 ;
      RECT 973.160 0.840 973.440 1415.960 ;
      RECT 975.400 0.840 975.680 1415.960 ;
      RECT 977.640 0.840 977.920 1415.960 ;
      RECT 979.880 0.840 980.160 1415.960 ;
      RECT 982.120 0.840 982.400 1415.960 ;
      RECT 984.360 0.840 984.640 1415.960 ;
      RECT 986.600 0.840 986.880 1415.960 ;
      RECT 988.840 0.840 989.120 1415.960 ;
      RECT 991.080 0.840 991.360 1415.960 ;
      RECT 993.320 0.840 993.600 1415.960 ;
      RECT 995.560 0.840 995.840 1415.960 ;
      RECT 997.800 0.840 998.080 1415.960 ;
      RECT 1000.040 0.840 1000.320 1415.960 ;
      RECT 1002.280 0.840 1002.560 1415.960 ;
      RECT 1004.520 0.840 1004.800 1415.960 ;
      RECT 1006.760 0.840 1007.040 1415.960 ;
      RECT 1009.000 0.840 1009.280 1415.960 ;
      RECT 1011.240 0.840 1011.520 1415.960 ;
      RECT 1013.480 0.840 1013.760 1415.960 ;
      RECT 1015.720 0.840 1016.000 1415.960 ;
      RECT 1017.960 0.840 1018.240 1415.960 ;
      RECT 1020.200 0.840 1020.480 1415.960 ;
      RECT 1022.440 0.840 1022.720 1415.960 ;
      RECT 1024.680 0.840 1024.960 1415.960 ;
      RECT 1026.920 0.840 1027.200 1415.960 ;
      RECT 1029.160 0.840 1029.440 1415.960 ;
      RECT 1031.400 0.840 1031.680 1415.960 ;
      RECT 1033.640 0.840 1033.920 1415.960 ;
      RECT 1035.880 0.840 1036.160 1415.960 ;
      RECT 1038.120 0.840 1038.400 1415.960 ;
      RECT 1040.360 0.840 1040.640 1415.960 ;
      RECT 1042.600 0.840 1042.880 1415.960 ;
      RECT 1044.840 0.840 1045.120 1415.960 ;
      RECT 1047.080 0.840 1047.360 1415.960 ;
      RECT 1049.320 0.840 1049.600 1415.960 ;
      RECT 1051.560 0.840 1051.840 1415.960 ;
      RECT 1053.800 0.840 1054.080 1415.960 ;
      RECT 1056.040 0.840 1056.320 1415.960 ;
      RECT 1058.280 0.840 1058.560 1415.960 ;
      RECT 1060.520 0.840 1060.800 1415.960 ;
      RECT 1062.760 0.840 1063.040 1415.960 ;
      RECT 1065.000 0.840 1065.280 1415.960 ;
      RECT 1067.240 0.840 1067.520 1415.960 ;
      RECT 1069.480 0.840 1069.760 1415.960 ;
      RECT 1071.720 0.840 1072.000 1415.960 ;
      RECT 1073.960 0.840 1074.240 1415.960 ;
      RECT 1076.200 0.840 1076.480 1415.960 ;
      RECT 1078.440 0.840 1078.720 1415.960 ;
      RECT 1080.680 0.840 1080.960 1415.960 ;
      RECT 1082.920 0.840 1083.200 1415.960 ;
      RECT 1085.160 0.840 1085.440 1415.960 ;
      RECT 1087.400 0.840 1087.680 1415.960 ;
      RECT 1089.640 0.840 1089.920 1415.960 ;
      RECT 1091.880 0.840 1092.160 1415.960 ;
      RECT 1094.120 0.840 1094.400 1415.960 ;
      RECT 1096.360 0.840 1096.640 1415.960 ;
      RECT 1098.600 0.840 1098.880 1415.960 ;
      RECT 1100.840 0.840 1101.120 1415.960 ;
      RECT 1103.080 0.840 1103.360 1415.960 ;
      RECT 1105.320 0.840 1105.600 1415.960 ;
      RECT 1107.560 0.840 1107.840 1415.960 ;
      RECT 1109.800 0.840 1110.080 1415.960 ;
      RECT 1112.040 0.840 1112.320 1415.960 ;
      RECT 1114.280 0.840 1114.560 1415.960 ;
      RECT 1116.520 0.840 1116.800 1415.960 ;
      RECT 1118.760 0.840 1119.040 1415.960 ;
      RECT 1121.000 0.840 1121.280 1415.960 ;
      RECT 1123.240 0.840 1123.520 1415.960 ;
      RECT 1125.480 0.840 1125.760 1415.960 ;
      RECT 1127.720 0.840 1128.000 1415.960 ;
      RECT 1129.960 0.840 1130.240 1415.960 ;
      RECT 1132.200 0.840 1132.480 1415.960 ;
      RECT 1134.440 0.840 1134.720 1415.960 ;
      RECT 1136.680 0.840 1136.960 1415.960 ;
      RECT 1138.920 0.840 1139.200 1415.960 ;
      RECT 1141.160 0.840 1141.440 1415.960 ;
      RECT 1143.400 0.840 1143.680 1415.960 ;
      RECT 1145.640 0.840 1145.920 1415.960 ;
      RECT 1147.880 0.840 1148.160 1415.960 ;
      RECT 1150.120 0.840 1150.400 1415.960 ;
      RECT 1152.360 0.840 1152.640 1415.960 ;
      RECT 1154.600 0.840 1154.880 1415.960 ;
      RECT 1156.840 0.840 1157.120 1415.960 ;
      RECT 1159.080 0.840 1159.360 1415.960 ;
      RECT 1161.320 0.840 1161.600 1415.960 ;
    END
  END VDD
  OBS
    LAYER metal1 ;
    RECT 0 0 1162.420 1416.800 ;
    LAYER metal2 ;
    RECT 0 0 1162.420 1416.800 ;
    LAYER metal3 ;
    RECT 0 0 1162.420 1416.800 ;
    LAYER metal4 ;
    RECT 0 0 1162.420 1416.800 ;
    LAYER OVERLAP ;
    RECT 0 0 1162.420 1416.800 ;
  END
END fakeram_w16_l32768

END LIBRARY
